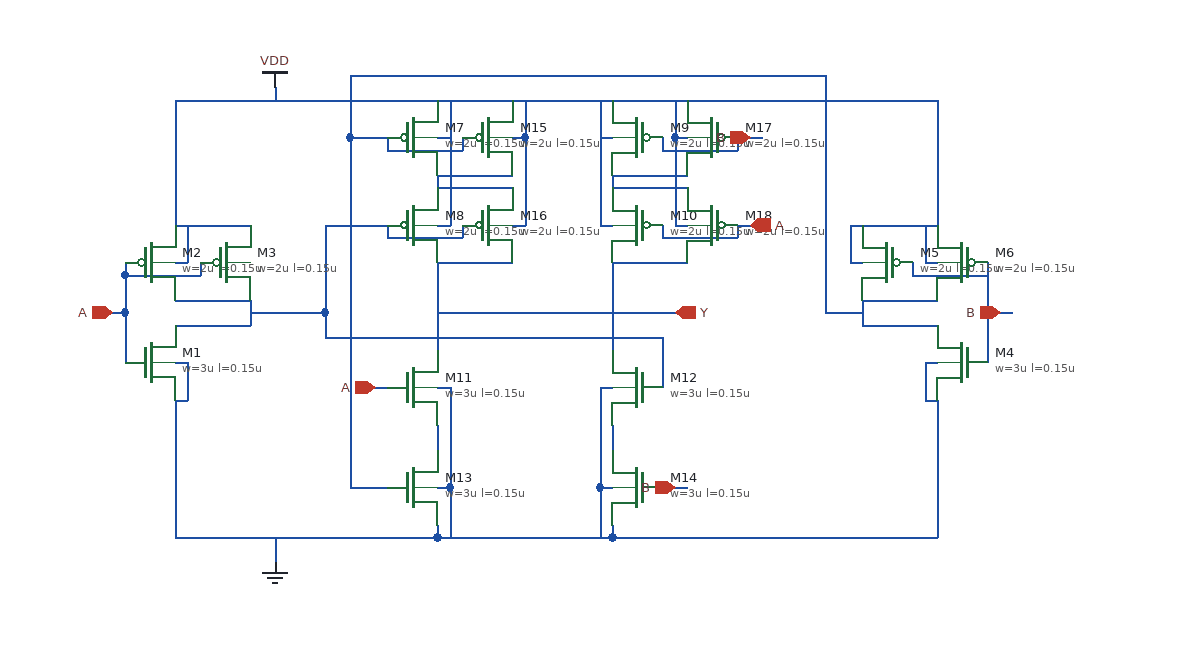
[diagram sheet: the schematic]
v {xschem version=3.0.0 file_version=1.2 }
G {}
K {}
V {}
S {}
E {}
N 80 -40 80 -30 {
lab=A}
N 80 -30 140 -30 {
lab=A}
N 140 -40 140 -30 {
lab=A}
N 120 -70 180 -70 {
lab=VDD}
N 120 -10 180 -10 {
lab=#net1}
N 70 0 80 0 {
lab=A}
N 80 -30 80 0 {
lab=A}
N 80 0 80 40 {
lab=A}
N 120 10 180 10 {
lab=#net1}
N 180 -10 180 10 {
lab=#net1}
N 180 0 210 -0 {
lab=#net1}
N 670 -70 730 -70 {
lab=VDD}
N 670 -10 730 -10 {
lab=#net2}
N 770 -40 770 40 {
lab=#net3}
N 720 40 730 40 {
lab=GND}
N 720 40 720 70 {
lab=GND}
N 720 70 730 70 {
lab=GND}
N 710 -30 770 -30 {
lab=#net3}
N 710 -40 710 -30 {
lab=#net3}
N 720 -40 730 -40 {
lab=VDD}
N 720 -70 720 -40 {
lab=VDD}
N 660 -40 670 -40 {
lab=VDD}
N 660 -70 660 -40 {
lab=VDD}
N 660 -70 670 -70 {
lab=VDD}
N 670 10 730 10 {
lab=#net2}
N 670 -10 670 10 {
lab=#net2}
N 640 0 670 -0 {
lab=#net2}
N 330 170 330 180 {
lab=GND}
N 330 180 470 180 {
lab=GND}
N 470 170 470 180 {
lab=GND}
N 470 90 470 110 {
lab=#net4}
N 330 90 330 110 {
lab=#net5}
N 330 140 340 140 {
lab=GND}
N 340 140 340 180 {
lab=GND}
N 460 140 470 140 {
lab=GND}
N 460 140 460 180 {
lab=GND}
N 330 60 340 60 {
lab=GND}
N 340 60 340 140 {
lab=GND}
N 460 60 470 60 {
lab=GND}
N 460 60 460 140 {
lab=GND}
N 330 -30 330 30 {
lab=Y}
N 330 0 530 0 {
lab=Y}
N 470 -110 470 -100 {
lab=#net7}
N 330 -110 330 -100 {
lab=#net8}
N 330 -170 470 -170 {
lab=VDD}
N 470 -100 530 -100 {
lab=#net7}
N 470 -170 530 -170 {
lab=VDD}
N 570 -140 570 -130 {
lab=B}
N 510 -130 570 -130 {
lab=B}
N 510 -140 510 -130 {
lab=B}
N 570 -70 570 -60 {
lab=A}
N 510 -60 570 -60 {
lab=A}
N 510 -70 510 -60 {
lab=A}
N 470 -40 530 -40 {
lab=#net6}
N 470 -110 530 -110 {
lab=#net7}
N 520 -140 530 -140 {
lab=VDD}
N 520 -170 520 -140 {
lab=VDD}
N 520 -70 530 -70 {
lab=VDD}
N 520 -140 520 -70 {
lab=VDD}
N 460 -70 470 -70 {
lab=VDD}
N 460 -170 460 -70 {
lab=VDD}
N 460 -140 470 -140 {
lab=VDD}
N 400 -170 400 -140 {
lab=VDD}
N 400 -140 400 -70 {
lab=VDD}
N 330 -100 380 -100 {
lab=#net8}
N 330 -110 380 -110 {
lab=#net8}
N 330 -40 380 -40 {
lab=Y}
N 330 -40 330 -30 {
lab=Y}
N 290 -70 290 -60 {
lab=#net1}
N 290 -60 350 -60 {
lab=#net1}
N 380 -40 390 -40 {
lab=Y}
N 350 -70 350 -60 {
lab=#net1}
N 330 -70 340 -70 {
lab=VDD}
N 340 -170 340 -70 {
lab=VDD}
N 330 -140 340 -140 {
lab=VDD}
N 290 -140 290 -130 {
lab=#net2}
N 290 -130 350 -130 {
lab=#net2}
N 350 -140 350 -130 {
lab=#net2}
N 380 -110 390 -110 {
lab=#net8}
N 380 -100 390 -100 {
lab=#net8}
N 390 -70 400 -70 {
lab=VDD}
N 390 -140 400 -140 {
lab=VDD}
N 120 70 120 180 {
lab=GND}
N 120 180 330 180 {
lab=GND}
N 730 70 730 180 {
lab=GND}
N 470 180 730 180 {
lab=GND}
N 120 -170 120 -70 {
lab=VDD}
N 120 -170 330 -170 {
lab=VDD}
N 730 -170 730 -70 {
lab=VDD}
N 530 -170 730 -170 {
lab=VDD}
N 210 -0 240 -0 {
lab=#net1}
N 240 -70 240 -0 {
lab=#net1}
N 240 -70 290 -70 {
lab=#net1}
N 240 -0 240 20 {
lab=#net1}
N 240 20 510 20 {
lab=#net1}
N 510 20 510 60 {
lab=#net1}
N 260 140 290 140 {
lab=#net2}
N 260 -140 260 140 {
lab=#net2}
N 260 -140 290 -140 {
lab=#net2}
N 260 -190 260 -140 {
lab=#net2}
N 260 -190 640 -190 {
lab=#net2}
N 640 -190 640 0 {
lab=#net2}
N 570 -70 590 -70 {
lab=A}
N 510 140 530 140 {
lab=B}
N 270 60 290 60 {
lab=A}
N 570 -140 590 -140 {
lab=B}
N 200 -180 200 -170 {
lab=VDD}
N 200 180 200 200 {
lab=GND}
N 770 0 790 0 {}
N 470 -40 470 -0 {}
N 470 0 470 30 {}
N 120 -40 130 -40 {}
N 130 -70 130 -40 {}
N 120 40 130 40 {}
N 130 40 130 70 {}
N 120 70 130 70 {}
C {nmos4-v.sym} 100 40 0 0 {name=M1 model=nmos w=3u l=0.15u m=1}
C {pmos4-v.sym} 100 -40 0 0 {name=M2 model=pmos w=2u l=0.15u m=1}
C {ipin.sym} 70 0 0 0 {name=p1 lab=A}
C {opin.sym} 520 0 0 0 {name=p2 lab=Y}
C {pmos4-v.sym} 160 -40 0 0 {name=M3 model=pmos w=2u l=0.15u m=1}
C {nmos4-v.sym} 750 40 2 0 {name=M4 model=nmos w=3u l=0.15u m=1}
C {pmos4-v.sym} 690 -40 2 0 {name=M5 model=pmos w=2u l=0.15u m=1}
C {ipin.sym} 780 0 2 0 {name=p3 lab=B}
C {pmos4-v.sym} 750 -40 2 0 {name=M6 model=pmos w=2u l=0.15u m=1}
C {pmos4-v.sym} 310 -140 0 0 {name=M7 model=pmos w=2u l=0.15u m=1}
C {pmos4-v.sym} 310 -70 0 0 {name=M8 model=pmos w=2u l=0.15u m=1}
C {pmos4-v.sym} 490 -140 2 0 {name=M9 model=pmos w=2u l=0.15u m=1}
C {pmos4-v.sym} 490 -70 2 0 {name=M10 model=pmos w=2u l=0.15u m=1}
C {nmos4-v.sym} 310 60 0 0 {name=M11 model=nmos w=3u l=0.15u m=1}
C {nmos4-v.sym} 490 60 2 0 {name=M12 model=nmos w=3u l=0.15u m=1}
C {nmos4-v.sym} 310 140 0 0 {name=M13 model=nmos w=3u l=0.15u m=1}
C {nmos4-v.sym} 490 140 2 0 {name=M14 model=nmos w=3u l=0.15u m=1}
C {pmos4-v.sym} 370 -140 0 0 {name=M15 model=pmos w=2u l=0.15u m=1}
C {pmos4-v.sym} 370 -70 0 0 {name=M16 model=pmos w=2u l=0.15u m=1}
C {pmos4-v.sym} 550 -140 2 0 {name=M17 model=pmos w=2u l=0.15u m=1}
C {pmos4-v.sym} 550 -70 2 0 {name=M18 model=pmos w=2u l=0.15u m=1}
C {ipin.sym} 580 -140 2 0 {name=p4 lab=B}
C {ipin.sym} 520 140 2 0 {name=p5 lab=B}
C {ipin.sym} 280 60 0 0 {name=p6 lab=A}
C {ipin.sym} 580 -70 0 1 {name=p7 lab=A}
C {vdd.sym} 200 -180 0 0 {name=l1 lab=VDD}
C {gnd.sym} 200 200 0 0 {name=l2 lab=GND}
